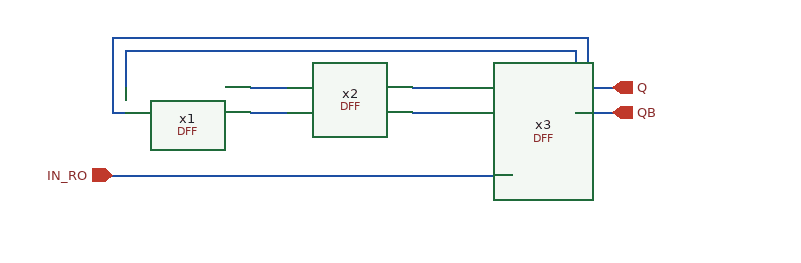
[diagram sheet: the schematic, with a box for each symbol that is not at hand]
v {xschem version=3.4.5 file_version=1.2
}
G {}
K {}
V {}
S {}
E {}
N 170 -40 200 -40 {
lab=#net1}
N 170 -20 200 -20 {
lab=#net2}
N 300 -70 300 -40 {
lab=Q}
N -60 -70 170 -70 {
lab=Q}
N -60 -70 -60 -40 {
lab=Q}
N -70 -20 -60 -20 {
lab=QB}
N -70 -70 -70 -20 {
lab=QB}
N -70 -80 -70 -70 {
lab=QB}
N -70 -80 180 -80 {
lab=QB}
N 310 -80 310 -20 {
lab=QB}
N 300 -20 310 -20 {
lab=QB}
N -70 30 -10 30 {
lab=IN_RO}
N -10 30 120 30 {
lab=IN_RO}
N 300 -40 330 -40 {
lab=Q}
N 310 -20 330 -20 {
lab=QB}
N 40 -40 70 -40 {
lab=#net3}
N 40 -20 70 -20 {
lab=#net4}
N 120 30 250 30 {
lab=IN_RO}
N 170 -70 300 -70 {
lab=Q}
N 180 -80 310 -80 {
lab=QB}
C {devices/opin.sym} 330 -40 0 0 {name=p1 lab=Q}
C {devices/ipin.sym} -70 30 0 0 {name=p2 lab=IN_RO}
C {devices/opin.sym} 330 -20 0 0 {name=p3 lab=QB}
C {/home/mstopyra/Documents/DTILO/schemas/DFF.sym} -10 -20 0 0 {name=x1}
C {/home/mstopyra/Documents/DTILO/schemas/DFF.sym} 120 -20 0 0 {name=x2}
C {/home/mstopyra/Documents/DTILO/schemas/DFF.sym} 250 -20 0 0 {name=x3}
